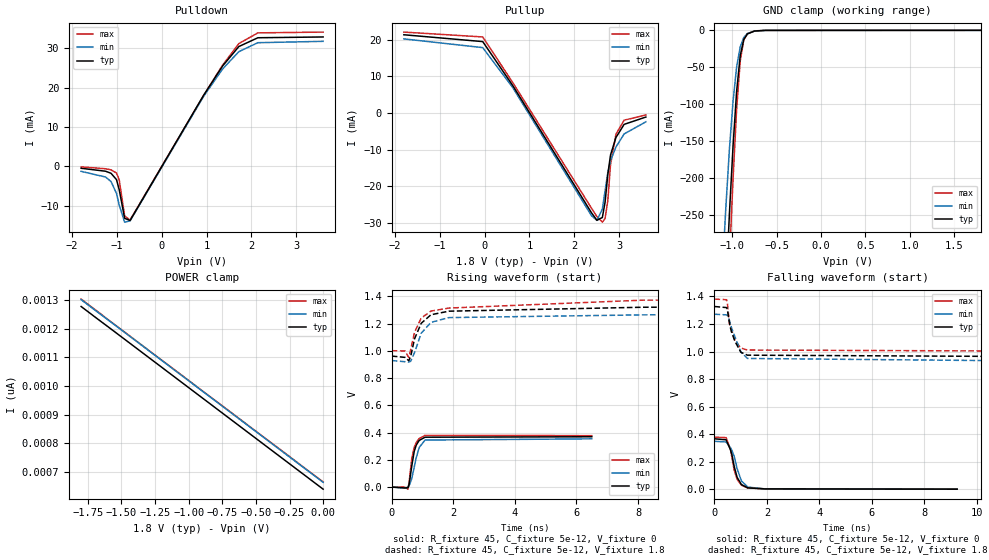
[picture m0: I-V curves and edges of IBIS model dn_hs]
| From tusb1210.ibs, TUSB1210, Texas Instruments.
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|   Model: dn_hs
|   Description:  DN in high-Speed mode
[Model]   dn_hs
Model_type   I/O
Polarity   Inverting
Enable   Active-High
Vmeas =   0.300
Vref =   0
Cref =   5e-12
Rref =   45
|variable   typ   min   max
C_comp   8.0p   7.14p   8.83p
[Receiver Thresholds]
Vcross_low =   -50m
Vcross_high =   500m
Vdiff_ac =   150m
Vdiff_dc =   100m
Tdiffslew_ac =   600p
[Temperature Range]   27   125   -40
[Voltage Range]   1.8   1.728   1.872
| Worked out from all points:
|   slope of the pulldown table from 0 to 0.27 V, typ, clamps not added: 50.6 ohm
|   slope of the pullup table from 0 to 0.27 V, typ, clamps not added: 58.4 ohm
|   GND clamp passes 1 mA (typ) near -0.75 V on its own axis
|   rising waveform, R_fixture 45, C_fixture 5e-12, V_fixture 0: 20-80 % time 172ps typ, 220ps min, 162ps max; typ from 0.001 V to 0.37 V
|   rising waveform, R_fixture 45, C_fixture 5e-12, V_fixture 1.8: 20-80 % time 499ps typ, 478ps min, 816ps max; typ from 0.962 V to 1.33 V
|   falling waveform, R_fixture 45, C_fixture 5e-12, V_fixture 0: 20-80 % time 296ps typ, 330ps min, 272ps max; typ from 0.367 V to 0.001 V
|   falling waveform, R_fixture 45, C_fixture 5e-12, V_fixture 1.8: 20-80 % time 322ps typ, 398ps min, 267ps max; typ from 1.33 V to 0.962 V
[GND Clamp]
| dn_hs
|Voltage   I(typ)   I(min)   I(max)
-1.8V     -2.571A    -2.176A    -2.872A
-1.112V   -460.6mA   -327.5mA   -556.3mA
-1.072V   -351.4mA   -239.8mA   -431.6mA
-1.032V   -248.8mA   -161.3mA   -312.3mA
-991mV    -156.9mA   -96.29mA   -201.7mA
-950.6mV  -82.5mA    -49.52mA   -107mA
-910.1mV  -34.34mA   -22.33mA   -41.35mA
-869.7mV  -12.47mA   -9.64mA    -12.7mA
-829.2mV  -4.861mA   -4.33mA    -4.529mA
-748.3mV  -947.7uA   -1.01mA    -769.6uA
-627mV    -70.16uA   -118.5uA   -34.18uA
1.8V      639.2pA    688.7pA    639pA
[POWER Clamp]
| dn_hs
|Voltage   I(typ)   I(min)   I(max)
-1.8V     1.278nA    1.302nA    1.304nA
-1.699V   1.242nA    1.266nA    1.268nA
-1.557V   1.192nA    1.216nA    1.217nA
0V        639.2pA    663.1pA    664.5pA
[Pulldown]
| dn_hs
|Voltage   I(typ)   I(min)   I(max)
-1.8V     -490.6uA   -1.273mA   -138.8uA
-1.254V   -1.247mA   -2.729mA   -619.8uA
-1.133V   -1.768mA   -3.868mA   -896.7uA
-1.011V   -3.378mA   -6.894mA   -1.704mA
-950.6mV  -5.918mA   -9.83mA    -3.386mA
-829.2mV  -13.22mA   -14.21mA   -12.63mA
-707.9mV  -13.78mA   -13.87mA   -13.65mA
930.3mV   18.02mA    17.75mA    17.96mA
1.355V    25.5mA     24.74mA    25.72mA
1.719V    30.47mA    29.17mA    31.23mA
2.144V    32.71mA    31.45mA    33.95mA
3.6V      32.91mA    31.8mA     34.15mA
[Pullup]
| dn_hs
|Voltage   I(typ)   I(min)   I(max)
-1.8V     21.4mA     20.27mA    22.13mA
-40.4mV   19.53mA    17.89mA    20.8mA
627mV     7.556mA    7.005mA    8.386mA
2.386V    -27.26mA   -28.05mA   -26mA
2.508V    -29.32mA   -29.35mA   -28.34mA
2.629V    -28.56mA   -26.26mA   -29.84mA
2.69V     -24.37mA   -21.23mA   -28.8mA
2.751V    -16.79mA   -16.3mA    -23.96mA
2.811V    -11.48mA   -13.05mA   -14.12mA
2.933V    -6.671mA   -9.267mA   -5.776mA
3.115V    -3.097mA   -5.713mA   -1.953mA
3.6V      -1.095mA   -2.399mA   -525.1uA
[Ramp]
| dn_hs
|variable   typ   min   max
dV/dt_r   0.366/1.686e-10   0.348/2.134e-10   0.378/1.624e-10
dV/dt_f   0.365/3.382e-10   0.341/4.263e-10   0.378/2.778e-10
R_load =   45
[Rising Waveform]
| dn_hs
R_fixture =   45
C_fixture =   5e-12
V_fixture =   0
V_fixture_min =   0
V_fixture_max =   0
|Time   V(typ)   V(min)   V(max)
0s        822.9uV    835.9uV    806.3uV
419.6ps   -5.59mV    -5.875mV   938uV
525.5ps   -4.134mV   -372.3uV   -14.49mV
564.8ps   21.71mV    11.22mV    37.9mV
649.8ps   155mV      62.48mV    211mV
728.9ps   261.9mV    147mV      291.8mV
793.7ps   308.3mV    215mV      327.2mV
889.6ps   342.9mV    290.7mV    356.8mV
1.081ns   367mV      346mV      380.5mV
6.498ns   370.1mV    355mV      378.4mV
[Rising Waveform]
| dn_hs
R_fixture =   45
C_fixture =   5e-12
V_fixture =   1.8
V_fixture_min =   1.728
V_fixture_max =   1.872
|Time   V(typ)   V(min)   V(max)
0s        962.4mV    929.6mV    1.002V
430.6ps   953mV      921mV      1V
554.2ps   928.4mV    917.9mV    951.2mV
616ps     961mV      924.9mV    1.011V
739.6ps   1.089V     987.8mV    1.137V
955.9ps   1.203V     1.13V      1.241V
1.274ns   1.266V     1.21V      1.293V
1.856ns   1.292V     1.245V     1.315V
8.165ns   1.321V     1.265V     1.373V
20.67ns   1.327V     1.271V     1.381V
[Falling Waveform]
| dn_hs
R_fixture =   45
C_fixture =   5e-12
V_fixture =   0
V_fixture_min =   0
V_fixture_max =   0
|Time   V(typ)   V(min)   V(max)
0s        366.6mV    348.5mV    378.4mV
444ps     359.1mV    343.4mV    374.9mV
608.9ps   286.3mV    301.9mV    288.8mV
661.4ps   253.2mV    282.3mV    234.7mV
748.1ps   167.5mV    240.4mV    141.2mV
860.8ps   87.27mV    151mV      73.29mV
1.024ns   34.79mV    60.88mV    29.13mV
1.268ns   10.14mV    16.12mV    9.51mV
1.919ns   2.859mV    2.498mV    3.396mV
9.249ns   824.6uV    849.8uV    806.3uV
[Falling Waveform]
| dn_hs
R_fixture =   45
C_fixture =   5e-12
V_fixture =   1.8
V_fixture_min =   1.728
V_fixture_max =   1.872
|Time   V(typ)   V(min)   V(max)
0s        1.327V     1.271V     1.381V
463.6ps   1.319V     1.266V     1.376V
490.2ps   1.304V     1.262V     1.355V
552.5ps   1.229V     1.236V     1.231V
588.1ps   1.188V     1.213V     1.181V
645.9ps   1.144V     1.174V     1.164V
779.3ps   1.074V     1.107V     1.08V
1.006ns   994.7mV    996.3mV    1.025V
1.255ns   973.6mV    949.8mV    1.011V
13.25ns   962.4mV    929.6mV    1.002V
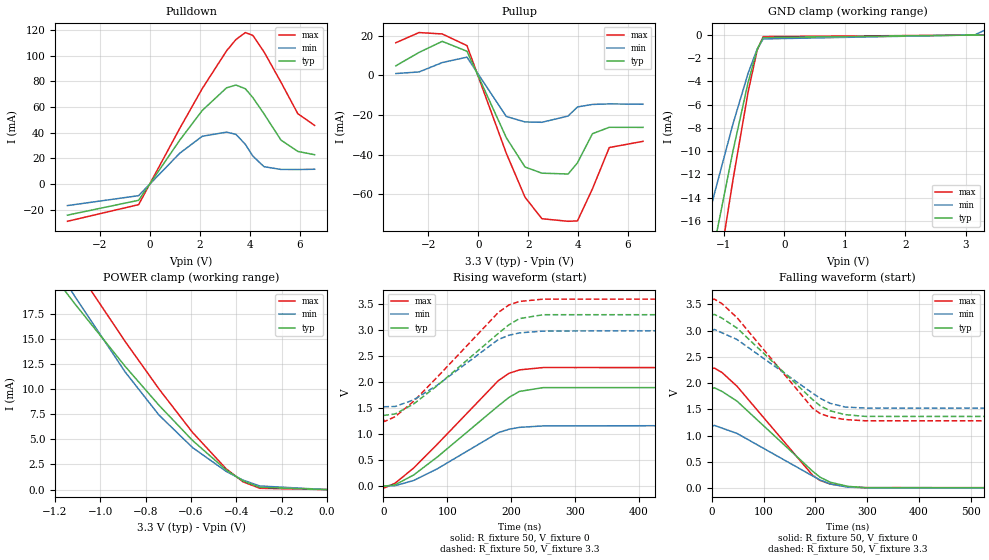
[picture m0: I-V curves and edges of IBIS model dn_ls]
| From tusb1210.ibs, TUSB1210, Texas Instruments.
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|   Model: dn_ls
|   Description:  DN in Low-Speed mode
[Model]   dn_ls
Model_type   I/O
Polarity   Inverting
Enable   Active-Low
Vinh =   2.000
Vinl =   0.800
Vmeas =   1.650
Vref =   0
Cref =   300e-12
Rref =   10e6
|variable   typ   min   max
C_comp   8.000p   7.140p   8.830p
[Receiver Thresholds]
Vcross_low =   1.3
Vcross_high =   2.0
Vdiff_ac =   200m
Vdiff_dc =   50m
Tdiffslew_ac =   300n
[Temperature Range]   27   125   -40
[Voltage Range]   3.3   3.0   3.6
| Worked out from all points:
|   slope of the pulldown table from 0 to 0.495 V, typ, clamps not added: 33.9 ohm
|   slope of the pullup table from 0 to 0.495 V, typ, clamps not added: 33.6 ohm
|   GND clamp passes 1 mA (typ) near -0.43 V on its own axis
|   POWER clamp passes 1 mA (typ) near -0.38 V on its own axis
|   rising waveform, R_fixture 50, V_fixture 0: 20-80 % time 112ns typ, 95ns min, 107ns max; typ from 0.006 V to 1.9 V
|   rising waveform, R_fixture 50, V_fixture 3.3: 20-80 % time 112ns typ, 95ns min, 107ns max; typ from 1.36 V to 3.29 V
|   falling waveform, R_fixture 50, V_fixture 0: 20-80 % time 122ns typ, 123ns min, 115ns max; typ from 1.9 V to 0.006 V
|   falling waveform, R_fixture 50, V_fixture 3.3: 20-80 % time 122ns typ, 123ns min, 115ns max; typ from 3.29 V to 1.36 V
[GND Clamp]
| dn_ls
|Voltage   I(typ)   I(min)   I(max)
-3.3V     -79.58mA   -61.62mA   -98.43mA
-1.6V     -30.23mA   -22.96mA   -37.77mA
-1.55V    -28.83mA   -21.89mA   -36.03mA
-1.35V    -23.26mA   -17.65mA   -29.11mA
-1.3V     -21.89mA   -16.61mA   -27.4mA
-1.15V    -17.82mA   -13.52mA   -22.32mA
-850mV    -9.988mA   -7.653mA   -12.47mA
-600mV    -4.077mA   -3.29mA    -4.92mA
-450mV    -1.247mA   -1.203mA   -1.298mA
-350mV    -209.5uA   -330.6uA   -134.3uA
3.15V     -6.302nA   14.99uA    -5.951pA
3.3V      2.821nA    380.8uA    20.54pA
[POWER Clamp]
| dn_ls
|Voltage   I(typ)   I(min)   I(max)
-3.3V     105.3mA    103.2mA    112.5mA
-1.261V   22.96mA    24.54mA    27.34mA
-1.224V   21.79mA    23.18mA    26.03mA
-1.187V   20.66mA    21.84mA    24.74mA
-1.112V   18.45mA    19.18mA    22.17mA
-889.9mV  12.23mA    11.67mA    14.7mA
-741.6mV  8.388mA    7.416mA    10.01mA
-593.3mV  4.886mA    4.176mA    5.683mA
-444.9mV  1.953mA    1.81mA     2.063mA
-370.8mV  869.6uA    944uA      781.4uA
-296.6mV  225.9uA    362uA      131.2uA
0V        2.821nA    64.57nA    508.9pA
[Pulldown]
| dn_ls
|Voltage   I(typ)   I(min)   I(max)
-3.3V     -24.26mA   -16.79mA   -29.05mA
-450mV    -12.66mA   -9.071mA   -16.07mA
1.2V      34.26mA    24.05mA    43.44mA
2.1V      57.38mA    37.25mA    74.44mA
3.075V    75.05mA    40.48mA    103.9mA
3.45V     77.17mA    38.72mA    112.7mA
3.825V    74.32mA    30.96mA    118.1mA
4.125V    67.43mA    21.79mA    115.9mA
4.575V    54.67mA    13.52mA    103mA
5.25V     34.32mA    11.39mA    79.46mA
5.925V    25.45mA    11.32mA    54.89mA
6.6V      22.86mA    11.53mA    45.71mA
[Pullup]
| dn_ls
|Voltage   I(typ)   I(min)   I(max)
-3.3V     4.817mA    932uA      16.45mA
-2.37V    11.57mA    1.733mA    21.58mA
-1.44V    17.15mA    6.453mA    20.88mA
-450mV    12.17mA    9.19mA     15mA
1.125V    -31.43mA   -20.71mA   -39.28mA
1.875V    -46.18mA   -23.47mA   -61.42mA
2.55V     -49.29mA   -23.65mA   -72.25mA
3.6V      -49.71mA   -20.49mA   -73.55mA
3.975V    -44.09mA   -15.91mA   -73.34mA
4.575V    -29.39mA   -14.64mA   -57.2mA
5.25V     -26.17mA   -14.38mA   -36.36mA
6.6V      -26.2mA    -14.55mA   -33.25mA
[Ramp]
| dn_ls
|variable   typ   min   max
dV/dt_r   1.890/1.116e-07   1.168/9.496e-08   2.271/1.068e-07
dV/dt_f   1.930/1.221e-07   1.473/1.232e-07   2.310/1.155e-07
R_load =   50
[Rising Waveform]
| dn_ls
R_fixture =   50
V_fixture =   0
V_fixture_min =   0
V_fixture_max =   0
|Time   V(typ)   V(min)   V(max)
0s        5.744mV    4.231mV    7.585mV
1.656ns   4.577mV    8.553mV    -28.92mV
18.24ns   29.54mV    12.82mV    60.25mV
47.27ns   217.3mV    112.3mV    350.9mV
84.6ns    564.6mV    338.1mV    810.7mV
180ns     1.543V     1.03V      2.027V
196.6ns   1.705V     1.095V     2.168V
213.2ns   1.822V     1.132V     2.235V
250.5ns   1.895V     1.16V      2.28V
823.3ns   1.896V     1.172V     2.279V
[Rising Waveform]
| dn_ls
R_fixture =   50
V_fixture =   3.3
V_fixture_min =   3.0
V_fixture_max =   3.6
|Time   V(typ)   V(min)   V(max)
0s        1.364V     1.522V     1.282V
1.656ns   1.363V     1.528V     1.245V
18.24ns   1.389V     1.533V     1.336V
47.27ns   1.58V      1.659V     1.631V
84.6ns    1.935V     1.944V     2.099V
180ns     2.934V     2.817V     3.336V
196.6ns   3.099V     2.899V     3.48V
213.2ns   3.219V     2.945V     3.548V
250.5ns   3.294V     2.98V      3.593V
823.3ns   3.294V     2.996V     3.592V
[Falling Waveform]
| dn_ls
R_fixture =   50
V_fixture =   0
V_fixture_min =   0
V_fixture_max =   0
|Time   V(typ)   V(min)   V(max)
0s        1.896V     1.172V     2.279V
4.868ns   1.912V     1.196V     2.288V
19.46ns   1.844V     1.144V     2.205V
48.64ns   1.657V     1.042V     1.941V
194.5ns   323.1mV    232.1mV    245.7mV
209.1ns   207.3mV    154.7mV    144.2mV
228.6ns   112.2mV    77.31mV    77.78mV
262.6ns   32.87mV    18.1mV     26.36mV
296.6ns   7.605mV    6.292mV    8.666mV
963.5ns   5.744mV    4.231mV    7.585mV
[Falling Waveform]
| dn_ls
R_fixture =   50
V_fixture =   3.3
V_fixture_min =   3.0
V_fixture_max =   3.6
|Time   V(typ)   V(min)   V(max)
0s        3.294V     2.996V     3.592V
4.868ns   3.311V     3.025V     3.602V
19.46ns   3.241V     2.961V     3.517V
48.64ns   3.05V      2.832V     3.249V
194.5ns   1.688V     1.81V      1.524V
209.1ns   1.57V      1.712V     1.421V
228.6ns   1.473V     1.615V     1.354V
257.7ns   1.4V       1.545V     1.306V
296.6ns   1.366V     1.525V     1.283V
963.5ns   1.364V     1.522V     1.282V
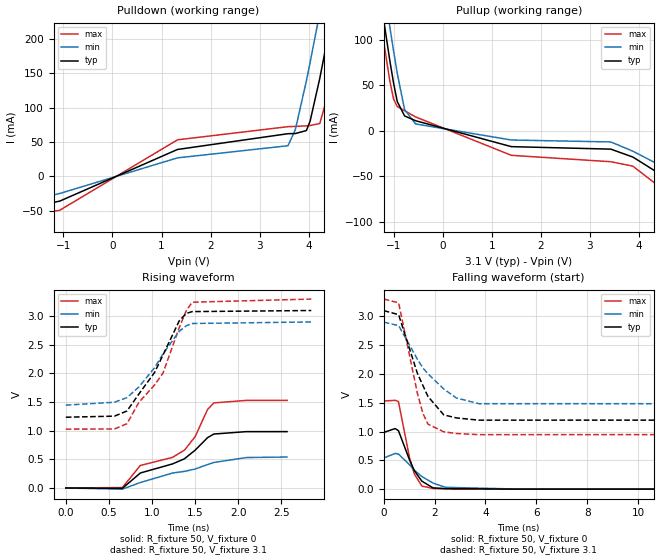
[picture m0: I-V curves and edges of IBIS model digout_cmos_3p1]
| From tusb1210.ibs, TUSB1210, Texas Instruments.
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|   Model: digout_cmos_3p1
|   Description:  OD_OS Output, CMOS mode
[Model]   digout_cmos_3p1
Model_type   Output
Polarity   Non-Inverting
Vmeas =   1.550
Vref =   0
Cref =   5e-12
Rref =   10e6
|variable   typ   min   max
C_comp   223.745p   130.866p   352.017p
[Temperature Range]   27   125   -40
[Voltage Range]   3.1   2.9   3.3
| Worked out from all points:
|   slope of the pulldown table from 0 to 0.465 V, typ, clamps not added: 29.3 ohm
|   slope of the pullup table from 0 to 0.465 V, typ, clamps not added: 61.3 ohm
|   rising waveform, R_fixture 50, V_fixture 0: 20-80 % time 773ps typ, 809ps min, 796ps max; typ from 0 V to 0.985 V
|   rising waveform, R_fixture 50, V_fixture 3.1: 20-80 % time 410ps typ, 413ps min, 485ps max; typ from 1.24 V to 3.1 V
|   falling waveform, R_fixture 50, V_fixture 0: 20-80 % time 596ps typ, 925ps min, 448ps max; typ from 0.985 V to 0 V
|   falling waveform, R_fixture 50, V_fixture 3.1: 20-80 % time 915ps typ, 1.46ns min, 642ps max; typ from 3.1 V to 1.24 V
[Pulldown]
| digout_cmos_3p1
|Voltage   I(typ)   I(min)   I(max)
-3.1V     -64mA      -58.56mA   -71.57mA
-1.075V   -35.83mA   -24.72mA   -49.08mA
1.325V    39.24mA    27.05mA    53.25mA
3.575V    62.13mA    44.65mA    72.33mA
3.725V    62.38mA    67.89mA    72.72mA
3.95V     66.68mA    138.8mA    73.52mA
4.025V    80.05mA    165.3mA    74.04mA
4.223V    142.5mA    237.8mA    76.94mA
4.42V     214.7mA    312.3mA    126.4mA
4.618V    289.5mA    387.8mA    198.3mA
4.816V    365.5mA    464.1mA    273.6mA
6.2V      908.1mA    1.006A     817.2mA
[Pullup]
| digout_cmos_3p1
|Voltage   I(typ)   I(min)   I(max)
-3.1V     858.2mA    893.1mA    836mA
-1.278V   149.2mA    187.1mA    124.8mA
-1.075V   76.9mA     113.8mA    54.58mA
-1V       52.65mA    87.9mA     35.08mA
-925mV    32.24mA    63.36mA    26.69mA
-775mV    16.33mA    23.31mA    22.01mA
-550mV    11.07mA    7.529mA    15.22mA
1.4V      -17.38mA   -10.1mA    -26.91mA
3.425V    -20.12mA   -12.21mA   -33.94mA
3.875V    -28.81mA   -22.39mA   -38.83mA
5.211V    -74.03mA   -59.71mA   -94.44mA
6.2V      -85.27mA   -72.01mA   -106.2mA
[Ramp]
| digout_cmos_3p1
|variable   typ   min   max
dV/dt_r   0.985/7.730e-10   0.541/8.093e-10   1.530/7.966e-10
dV/dt_f   1.864/9.154e-10   1.453/1.456e-09   2.272/6.417e-10
R_load =   50
[Rising Waveform]
| digout_cmos_3p1
R_fixture =   50
V_fixture =   0
V_fixture_min =   0
V_fixture_max =   0
|Time   V(typ)   V(min)   V(max)
0s        18.1nV     23.07nV    48.13nV
655.8ps   -6.583mV   -20.68mV   7.209mV
864.5ps   261.8mV    95.27mV    393.6mV
1.237ns   420.1mV    260.9mV    534.3mV
1.375ns   509.1mV    289.9mV    659.6mV
1.5ns     660.5mV    330.7mV    896.3mV
1.644ns   879.2mV    409mV      1.371V
1.717ns   942.5mV    445.8mV    1.486V
2.094ns   984.2mV    531.7mV    1.53V
2.566ns   984.6mV    540.7mV    1.53V
[Rising Waveform]
| digout_cmos_3p1
R_fixture =   50
V_fixture =   3.1
V_fixture_min =   2.9
V_fixture_max =   3.3
|Time   V(typ)   V(min)   V(max)
0s        1.236V     1.447V     1.028V
564.3ps   1.255V     1.498V     1.031V
709.5ps   1.345V     1.578V     1.123V
848.2ps   1.643V     1.766V     1.497V
1.029ns   2.016V     2.099V     1.798V
1.126ns   2.319V     2.339V     2.003V
1.315ns   2.918V     2.737V     2.798V
1.396ns   3.048V     2.833V     3.094V
1.466ns   3.081V     2.873V     3.245V
2.847ns   3.1V       2.9V       3.3V
[Falling Waveform]
| digout_cmos_3p1
R_fixture =   50
V_fixture =   0
V_fixture_min =   0
V_fixture_max =   0
|Time   V(typ)   V(min)   V(max)
0s        984.6mV    540.9mV    1.53V
449.6ps   1.052V     620.5mV    1.542V
578.9ps   1.016V     609.2mV    1.521V
1.02ns    502.5mV    423mV      534.9mV
1.204ns   321.3mV    328.1mV    264.3mV
1.499ns   139.3mV    219.4mV    53.67mV
1.941ns   21.62mV    105.2mV    12.04mV
2.428ns   9.526mV    32.08mV    6.143mV
5.309ns   498.4uV    1.512mV    165.4uV
64.04ns   334.9nV    427nV      271nV
[Falling Waveform]
| digout_cmos_3p1
R_fixture =   50
V_fixture =   3.1
V_fixture_min =   2.9
V_fixture_max =   3.3
|Time   V(typ)   V(min)   V(max)
0s        3.1V       2.9V       3.3V
586.5ps   3.029V     2.839V     3.235V
1.324ns   2.011V     2.255V     1.663V
1.543ns   1.797V     2.103V     1.314V
1.741ns   1.609V     2.002V     1.128V
2.36ns    1.29V      1.739V     995.6mV
2.854ns   1.237V     1.583V     966.5mV
3.74ns    1.198V     1.484V     946.2mV
896.8ns   1.236V     1.447V     1.025V
7.884us   1.236V     1.447V     1.028V
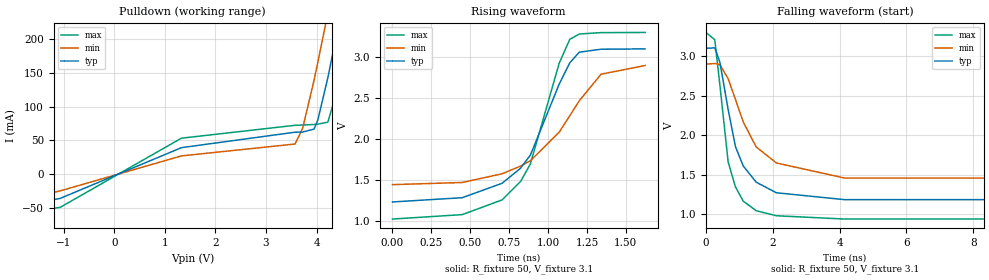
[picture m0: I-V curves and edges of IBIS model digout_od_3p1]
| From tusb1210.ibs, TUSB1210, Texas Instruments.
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|   Model: digout_od_3p1
|   Description:  OD_OS Output, OD mode
[Model]   digout_od_3p1
Model_type   Open_drain
Polarity   Non-Inverting
Vmeas =   1.550
Vref =   3.1
Cref =   5e-12
Rref =   100
|variable   typ   min   max
C_comp   0.001p   0.001p   0.001p
[Temperature Range]   27   125   -40
[Voltage Range]   3.1   2.9   3.3
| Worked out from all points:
|   slope of the pulldown table from 0 to 0.465 V, typ, clamps not added: 29.3 ohm
|   rising waveform, R_fixture 50, V_fixture 3.1: 20-80 % time 283ps typ, 368ps min, 237ps max; typ from 1.24 V to 3.1 V
|   falling waveform, R_fixture 50, V_fixture 3.1: 20-80 % time 612ps typ, 1.03ns min, 394ps max; typ from 3.1 V to 1.24 V
[Pulldown]
| digout_od_3p1
|Voltage   I(typ)   I(min)   I(max)
-3.1V     -64mA      -58.56mA   -71.57mA
-1.075V   -35.83mA   -24.72mA   -49.08mA
1.325V    39.24mA    27.05mA    53.25mA
3.575V    62.13mA    44.65mA    72.33mA
3.725V    62.38mA    67.89mA    72.72mA
3.95V     66.68mA    138.8mA    73.52mA
4.025V    80.05mA    165.3mA    74.04mA
4.223V    142.5mA    237.8mA    76.94mA
4.42V     214.7mA    312.3mA    126.4mA
4.618V    289.5mA    387.8mA    198.3mA
4.816V    365.5mA    464.1mA    273.6mA
6.2V      908.1mA    1.006A     817.2mA
[Ramp]
| digout_od_3p1
|variable   typ   min   max
dV/dt_r   1.864/2.832e-10   1.453/3.685e-10   2.272/2.368e-10
dV/dt_f   1.864/6.122e-10   1.453/1.034e-09   2.272/3.936e-10
R_load =   50
[Rising Waveform]
| digout_od_3p1
R_fixture =   50
V_fixture =   3.1
V_fixture_min =   2.9
V_fixture_max =   3.3
|Time   V(typ)   V(min)   V(max)
0s        1.236V     1.447V     1.028V
448.6ps   1.288V     1.473V     1.082V
704.3ps   1.463V     1.579V     1.261V
823ps     1.646V     1.672V     1.484V
886.7ps   1.807V     1.738V     1.699V
1.072ns   2.671V     2.086V     2.926V
1.14ns    2.93V      2.286V     3.216V
1.201ns   3.059V     2.468V     3.28V
1.341ns   3.095V     2.791V     3.297V
1.624ns   3.099V     2.897V     3.299V
[Falling Waveform]
| digout_od_3p1
R_fixture =   50
V_fixture =   3.1
V_fixture_min =   2.9
V_fixture_max =   3.3
|Time   V(typ)   V(min)   V(max)
0s        3.1V       2.9V       3.3V
266.8ps   3.105V     2.907V     3.208V
417.6ps   2.926V     2.894V     2.64V
666.8ps   2.325V     2.714V     1.662V
882.8ps   1.859V     2.455V     1.348V
1.119ns   1.61V      2.167V     1.166V
1.505ns   1.406V     1.852V     1.045V
2.11ns    1.272V     1.649V     981.4mV
4.157ns   1.185V     1.458V     939.6mV
4.555us   1.236V     1.447V     1.028V
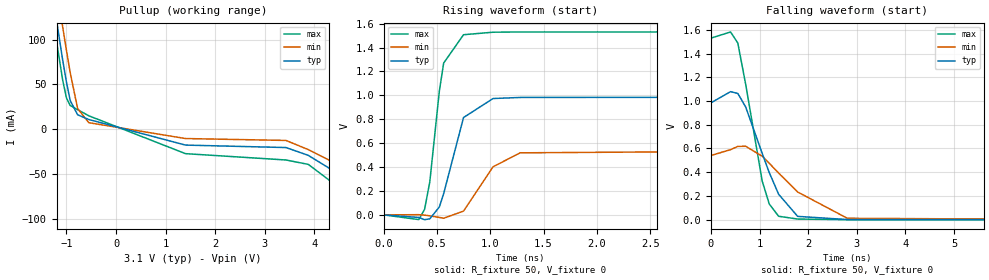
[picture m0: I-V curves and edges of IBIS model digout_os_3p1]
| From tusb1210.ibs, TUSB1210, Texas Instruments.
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|   Model: digout_os_3p1
|   Description:  OD_OS Output, OS mode
[Model]   digout_os_3p1
Model_type   Open_source
Polarity   Non-Inverting
Vmeas =   1.550
Vref =   0
Cref =   5e-12
Rref =   10e6
|variable   typ   min   max
C_comp   223.745p   130.866p   352.017p
[Temperature Range]   27   125   -40
[Voltage Range]   3.1   2.9   3.3
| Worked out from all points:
|   slope of the pullup table from 0 to 0.465 V, typ, clamps not added: 61.3 ohm
|   rising waveform, R_fixture 50, V_fixture 0: 20-80 % time 167ps typ, 247ps min, 116ps max; typ from 0 V to 0.985 V
|   falling waveform, R_fixture 50, V_fixture 0: 20-80 % time 555ps typ, 868ps min, 383ps max; typ from 0.985 V to 0 V
[Pullup]
| digout_os_3p1
|Voltage   I(typ)   I(min)   I(max)
-3.1V     858.2mA    893.1mA    836mA
-1.278V   149.2mA    187.1mA    124.8mA
-1.075V   76.9mA     113.8mA    54.58mA
-1V       52.65mA    87.9mA     35.08mA
-925mV    32.24mA    63.36mA    26.69mA
-775mV    16.33mA    23.31mA    22.01mA
-550mV    11.07mA    7.529mA    15.22mA
1.4V      -17.38mA   -10.1mA    -26.91mA
3.425V    -20.12mA   -12.21mA   -33.94mA
3.875V    -28.81mA   -22.39mA   -38.83mA
5.211V    -74.03mA   -59.71mA   -94.44mA
6.2V      -85.27mA   -72.01mA   -106.2mA
[Ramp]
| digout_os_3p1
|variable   typ   min   max
dV/dt_r   0.985/1.668e-10   0.541/2.457e-10   1.530/1.157e-10
dV/dt_f   0.985/5.520e-10   0.541/8.582e-10   1.530/3.824e-10
R_load =   50
[Rising Waveform]
| digout_os_3p1
R_fixture =   50
V_fixture =   0
V_fixture_min =   0
V_fixture_max =   0
|Time   V(typ)   V(min)   V(max)
0s        1.619nV    4.337nV    1.658nV
328.8ps   -21.61mV   1.496mV    -39.44mV
383.6ps   -40.27mV   -2.326mV   46.84mV
432.1ps   -33.32mV   -7.987mV   274.5mV
522ps     66.19mV    -21.53mV   1.036V
562.5ps   178mV      -28.2mV    1.27V
748.9ps   814.2mV    31.56mV    1.507V
1.026ns   973.3mV    402.3mV    1.528V
1.28ns    982.2mV    519mV      1.53V
5.015ns   984.6mV    540.9mV    1.53V
[Falling Waveform]
| digout_os_3p1
R_fixture =   50
V_fixture =   0
V_fixture_min =   0
V_fixture_max =   0
|Time   V(typ)   V(min)   V(max)
0s        984.6mV    540.9mV    1.53V
404.2ps   1.079V     590.2mV    1.582V
553ps     1.064V     617.5mV    1.489V
715.1ps   949.8mV    618.8mV    1.141V
1.055ns   558.6mV    535mV      325.6mV
1.2ns     396.7mV    475.5mV    132.2mV
1.393ns   214.2mV    392.7mV    28.76mV
1.784ns   27.94mV    233.4mV    5.427mV
2.806ns   971.9uV    11.85mV    88.08uV
8.296ns   19uV       10.71uV    27.02uV
